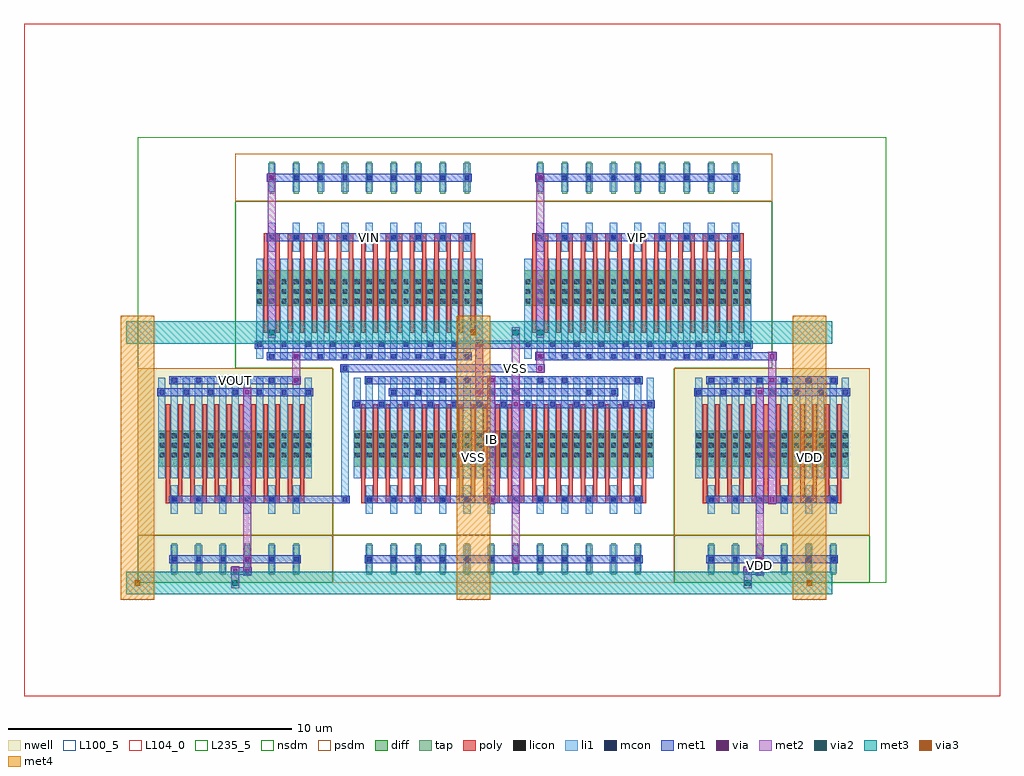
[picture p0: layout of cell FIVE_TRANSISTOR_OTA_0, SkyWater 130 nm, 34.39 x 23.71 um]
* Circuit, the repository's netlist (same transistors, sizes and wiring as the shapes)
* NGSPICE file created from FIVE_TRANSISTOR_OTA_0.ext - technology: sky130A

.subckt DCL_PMOS_S_13688038_X6_Y1_1774869037 a_200_252# w_0_0#
X0 w_0_0# a_200_252# a_200_252# w_0_0# sky130_fd_pr__pfet_01v8 ad=0.1764 pd=1.54 as=0.1764 ps=1.54 w=1.26 l=0.15 M=12
.ends

.subckt SCM_NMOS_16984956_X6_Y1_1774869040 a_402_441# a_200_252# a_147_441#
X0 a_147_441# a_200_252# a_200_252# a_147_441# sky130_fd_pr__nfet_01v8 ad=0.1764 pd=1.54 as=0.1764 ps=1.54 w=1.26 l=0.15 M=12
X1 a_147_441# a_200_252# a_402_441# a_147_441# sky130_fd_pr__nfet_01v8 ad=0.1764 pd=1.54 as=0.1764 ps=1.54 w=1.26 l=0.15 M=12
.ends

.subckt NMOS_4T_73049722_X9_Y1_1774869038 a_230_441# a_200_252# a_147_441# a_241_1232#
X0 a_147_441# a_200_252# a_230_441# a_241_1232# sky130_fd_pr__nfet_01v8 ad=0.1764 pd=1.54 as=0.1764 ps=1.54 w=1.26 l=0.15 M=18
.ends

.subckt PMOS_S_86315193_X6_Y1_1774869039 a_230_441# a_200_252# w_0_0#
X0 w_0_0# a_200_252# a_230_441# w_0_0# sky130_fd_pr__pfet_01v8 ad=0.1764 pd=1.54 as=0.1764 ps=1.54 w=1.26 l=0.15 M=12
.ends

.subckt FIVE_TRANSISTOR_OTA_0 IB VOUT VIP VIN VSS VDD
XDCL_PMOS_S_13688038_X6_Y1_1774869037_0 li_1437_571# VDD DCL_PMOS_S_13688038_X6_Y1_1774869037
XSCM_NMOS_16984956_X6_Y1_1774869040_0 m1_2376_1316# IB VSS SCM_NMOS_16984956_X6_Y1_1774869040
XNMOS_4T_73049722_X9_Y1_1774869038_0 VOUT VIN m1_2376_1316# VSS NMOS_4T_73049722_X9_Y1_1774869038
XNMOS_4T_73049722_X9_Y1_1774869038_1 li_1437_571# VIP m1_2376_1316# VSS NMOS_4T_73049722_X9_Y1_1774869038
XPMOS_S_86315193_X6_Y1_1774869039_0 VOUT li_1437_571# VDD PMOS_S_86315193_X6_Y1_1774869039
.ends

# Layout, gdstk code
from math import pi, radians
import gdstk
lib = gdstk.Library(unit=1e-6, precision=1e-09)
def R(c, l, rs):  # rectangles x0, y0, x1, y1
    for r in rs: c.add(gdstk.rectangle(r[:2], r[2:], *l))
def A(c, l, x, y, w, h, nx, ny, dx, dy):  # array of equal rectangles
    R(c, l, [(x+i*dx, y+j*dy, x+i*dx+w, y+j*dy+h) for i in range(nx) for j in range(ny)])
def P(c, l, *ps):  # polygons
    for p in ps: c.add(gdstk.Polygon(p, *l))
nwell = (64, 20)
diff = (65, 20)
tap = (65, 44)
poly = (66, 20)
licon = (66, 44)
li1 = (67, 20)
mcon = (67, 44)
met1 = (68, 20)
via = (68, 44)
met2 = (69, 20)
via2 = (69, 44)
met3 = (70, 20)
via3 = (70, 44)
met4 = (71, 20)
nsdm = (93, 44)
psdm = (94, 20)
L100_5 = (100, 5)
L104_0 = (104, 0)
L235_5 = (235, 5)

scm_nmos_16984956_x6_y1_ = lib.new_cell('SCM_NMOS_16984956_X6_Y1_1774869040')
R(scm_nmos_16984956_x6_y1_, diff, [(0.735,2.205,11.305,3.465)])
A(scm_nmos_16984956_x6_y1_, tap, 1.205, 6.16, 0.17, 1.12, 12, 1, 0.86, 0)
A(scm_nmos_16984956_x6_y1_, poly, 1, 1.26, 0.15, 3.36, 24, 1, 0.43, 0)
A(scm_nmos_16984956_x6_y1_, poly, 1, 4.485, 0.58, 0.27, 12, 1, 0.86, 0)
A(scm_nmos_16984956_x6_y1_, licon, 0.775, 2.285, 0.17, 0.17, 3, 3, 0.43, 0.34)
A(scm_nmos_16984956_x6_y1_, licon, 1.635, 2.285, 0.17, 0.17, 3, 3, 0.43, 0.34)
A(scm_nmos_16984956_x6_y1_, licon, 2.495, 2.285, 0.17, 0.17, 3, 3, 0.43, 0.34)
A(scm_nmos_16984956_x6_y1_, licon, 3.355, 2.285, 0.17, 0.17, 3, 3, 0.43, 0.34)
A(scm_nmos_16984956_x6_y1_, licon, 4.215, 2.285, 0.17, 0.17, 3, 3, 0.43, 0.34)
A(scm_nmos_16984956_x6_y1_, licon, 5.075, 2.285, 0.17, 0.17, 3, 3, 0.43, 0.34)
A(scm_nmos_16984956_x6_y1_, licon, 5.935, 2.285, 0.17, 0.17, 3, 3, 0.43, 0.34)
A(scm_nmos_16984956_x6_y1_, licon, 6.795, 2.285, 0.17, 0.17, 3, 3, 0.43, 0.34)
A(scm_nmos_16984956_x6_y1_, licon, 7.655, 2.285, 0.17, 0.17, 3, 3, 0.43, 0.34)
A(scm_nmos_16984956_x6_y1_, licon, 8.515, 2.285, 0.17, 0.17, 3, 3, 0.43, 0.34)
A(scm_nmos_16984956_x6_y1_, licon, 9.375, 2.285, 0.17, 0.17, 3, 3, 0.43, 0.34)
A(scm_nmos_16984956_x6_y1_, licon, 10.235, 2.285, 0.17, 0.17, 3, 3, 0.43, 0.34)
A(scm_nmos_16984956_x6_y1_, licon, 1.205, 4.535, 0.17, 0.17, 12, 2, 0.86, 2.1)
A(scm_nmos_16984956_x6_y1_, li1, 0.735, 0.335, 0.25, 3.53, 25, 1, 0.43, 0)
A(scm_nmos_16984956_x6_y1_, li1, 1.165, 4.115, 0.25, 1.01, 12, 2, 0.86, 2.1)
A(scm_nmos_16984956_x6_y1_, mcon, 0.775, 1.175, 0.17, 0.17, 13, 1, 0.86, 0)
A(scm_nmos_16984956_x6_y1_, mcon, 1.205, 4.535, 0.17, 0.17, 12, 2, 0.86, 2.1)
R(scm_nmos_16984956_x6_y1_, mcon, [(1.205,0.335,1.375,0.505), (3.785,0.335,3.955,0.505), (4.645,0.335,4.815,0.505), (7.225,0.335,7.395,0.505), (8.085,0.335,8.255,0.505), (10.665,0.335,10.835,0.505), (2.065,0.755,2.235,0.925), (2.925,0.755,3.095,0.925), (5.505,0.755,5.675,0.925), (6.365,0.755,6.535,0.925), (8.945,0.755,9.115,0.925), (9.805,0.755,9.975,0.925)])
R(scm_nmos_16984956_x6_y1_, met1, [(1.12,0.28,10.92,0.56), (1.98,0.7,10.06,0.98), (0.69,1.12,11.35,1.4), (1.12,4.48,10.92,4.76), (1.12,6.58,10.92,6.86)])
R(scm_nmos_16984956_x6_y1_, via, [(5.515,0.345,5.665,0.495), (6.375,1.185,6.525,1.335), (5.515,4.545,5.665,4.695), (6.375,6.645,6.525,6.795)])
R(scm_nmos_16984956_x6_y1_, met2, [(5.45,0.26,5.73,4.78), (6.31,1.1,6.59,6.88)])
R(scm_nmos_16984956_x6_y1_, nsdm, [(0,0,12.04,5.88)])
R(scm_nmos_16984956_x6_y1_, psdm, [(0,5.88,12.04,7.56)])
R(scm_nmos_16984956_x6_y1_, L100_5, [(0,0,12.04,7.56)])

dcl_pmos_s_13688038_x6_y = lib.new_cell('DCL_PMOS_S_13688038_X6_Y1_1774869037')
R(dcl_pmos_s_13688038_x6_y, nwell, [(0,0,6.88,7.56)])
R(dcl_pmos_s_13688038_x6_y, diff, [(0.735,2.205,6.145,3.465)])
A(dcl_pmos_s_13688038_x6_y, tap, 1.205, 6.16, 0.17, 1.12, 6, 1, 0.86, 0)
A(dcl_pmos_s_13688038_x6_y, poly, 1, 1.26, 0.15, 3.36, 12, 1, 0.43, 0)
A(dcl_pmos_s_13688038_x6_y, poly, 1, 4.485, 0.58, 0.27, 6, 1, 0.86, 0)
A(dcl_pmos_s_13688038_x6_y, licon, 0.775, 2.285, 0.17, 0.17, 3, 3, 0.43, 0.34)
A(dcl_pmos_s_13688038_x6_y, licon, 1.635, 2.285, 0.17, 0.17, 3, 3, 0.43, 0.34)
A(dcl_pmos_s_13688038_x6_y, licon, 2.495, 2.285, 0.17, 0.17, 3, 3, 0.43, 0.34)
A(dcl_pmos_s_13688038_x6_y, licon, 3.355, 2.285, 0.17, 0.17, 3, 3, 0.43, 0.34)
A(dcl_pmos_s_13688038_x6_y, licon, 4.215, 2.285, 0.17, 0.17, 3, 3, 0.43, 0.34)
A(dcl_pmos_s_13688038_x6_y, licon, 5.075, 2.285, 0.17, 0.17, 3, 3, 0.43, 0.34)
A(dcl_pmos_s_13688038_x6_y, licon, 1.205, 4.535, 0.17, 0.17, 6, 2, 0.86, 2.1)
A(dcl_pmos_s_13688038_x6_y, li1, 0.735, 0.335, 0.25, 3.53, 13, 1, 0.43, 0)
A(dcl_pmos_s_13688038_x6_y, li1, 1.165, 4.115, 0.25, 1.01, 6, 2, 0.86, 2.1)
A(dcl_pmos_s_13688038_x6_y, mcon, 1.205, 0.335, 0.17, 0.17, 6, 2, 0.86, 4.2)
A(dcl_pmos_s_13688038_x6_y, mcon, 0.775, 0.755, 0.17, 0.17, 7, 1, 0.86, 0)
A(dcl_pmos_s_13688038_x6_y, mcon, 1.205, 6.635, 0.17, 0.17, 6, 1, 0.86, 0)
R(dcl_pmos_s_13688038_x6_y, met1, [(1.12,0.28,5.76,0.56), (0.69,0.7,6.19,0.98), (1.12,4.48,5.76,4.76), (1.12,6.58,5.76,6.86)])
R(dcl_pmos_s_13688038_x6_y, via, [(3.365,0.345,3.515,0.495), (3.795,0.765,3.945,0.915), (3.365,4.545,3.515,4.695), (3.795,6.645,3.945,6.795)])
R(dcl_pmos_s_13688038_x6_y, met2, [(3.3,0.26,3.58,4.78), (3.73,0.68,4.01,6.88)])
R(dcl_pmos_s_13688038_x6_y, nsdm, [(0,5.88,6.88,7.56)])
R(dcl_pmos_s_13688038_x6_y, psdm, [(0,0,6.88,5.88)])
R(dcl_pmos_s_13688038_x6_y, L100_5, [(0,0,6.88,7.56)])

pmos_s_86315193_x6_y1_17 = lib.new_cell('PMOS_S_86315193_X6_Y1_1774869039')
R(pmos_s_86315193_x6_y1_17, nwell, [(0,0,6.88,7.56)])
R(pmos_s_86315193_x6_y1_17, diff, [(0.735,2.205,6.145,3.465)])
A(pmos_s_86315193_x6_y1_17, tap, 1.205, 6.16, 0.17, 1.12, 6, 1, 0.86, 0)
A(pmos_s_86315193_x6_y1_17, poly, 1, 1.26, 0.15, 3.36, 12, 1, 0.43, 0)
A(pmos_s_86315193_x6_y1_17, poly, 1, 4.485, 0.58, 0.27, 6, 1, 0.86, 0)
A(pmos_s_86315193_x6_y1_17, licon, 0.775, 2.285, 0.17, 0.17, 3, 3, 0.43, 0.34)
A(pmos_s_86315193_x6_y1_17, licon, 1.635, 2.285, 0.17, 0.17, 3, 3, 0.43, 0.34)
A(pmos_s_86315193_x6_y1_17, licon, 2.495, 2.285, 0.17, 0.17, 3, 3, 0.43, 0.34)
A(pmos_s_86315193_x6_y1_17, licon, 3.355, 2.285, 0.17, 0.17, 3, 3, 0.43, 0.34)
A(pmos_s_86315193_x6_y1_17, licon, 4.215, 2.285, 0.17, 0.17, 3, 3, 0.43, 0.34)
A(pmos_s_86315193_x6_y1_17, licon, 5.075, 2.285, 0.17, 0.17, 3, 3, 0.43, 0.34)
A(pmos_s_86315193_x6_y1_17, licon, 1.205, 4.535, 0.17, 0.17, 6, 2, 0.86, 2.1)
A(pmos_s_86315193_x6_y1_17, li1, 0.735, 0.335, 0.25, 3.53, 13, 1, 0.43, 0)
A(pmos_s_86315193_x6_y1_17, li1, 1.165, 4.115, 0.25, 1.01, 6, 2, 0.86, 2.1)
A(pmos_s_86315193_x6_y1_17, mcon, 1.205, 0.335, 0.17, 0.17, 6, 2, 0.86, 4.2)
A(pmos_s_86315193_x6_y1_17, mcon, 0.775, 0.755, 0.17, 0.17, 7, 1, 0.86, 0)
A(pmos_s_86315193_x6_y1_17, mcon, 1.205, 6.635, 0.17, 0.17, 6, 1, 0.86, 0)
R(pmos_s_86315193_x6_y1_17, met1, [(1.12,0.28,5.76,0.56), (0.69,0.7,6.19,0.98), (1.12,4.48,5.76,4.76), (1.12,6.58,5.76,6.86)])
R(pmos_s_86315193_x6_y1_17, via, [(3.795,0.765,3.945,0.915), (3.795,6.645,3.945,6.795)])
R(pmos_s_86315193_x6_y1_17, met2, [(3.73,0.68,4.01,6.88)])
R(pmos_s_86315193_x6_y1_17, nsdm, [(0,5.88,6.88,7.56)])
R(pmos_s_86315193_x6_y1_17, psdm, [(0,0,6.88,5.88)])
R(pmos_s_86315193_x6_y1_17, L100_5, [(0,0,6.88,7.56)])

nmos_4t_73049722_x9_y1_1 = lib.new_cell('NMOS_4T_73049722_X9_Y1_1774869038')
R(nmos_4t_73049722_x9_y1_1, diff, [(0.735,2.205,8.725,3.465)])
A(nmos_4t_73049722_x9_y1_1, tap, 1.205, 6.16, 0.17, 1.12, 9, 1, 0.86, 0)
A(nmos_4t_73049722_x9_y1_1, poly, 1, 1.26, 0.15, 3.36, 18, 1, 0.43, 0)
A(nmos_4t_73049722_x9_y1_1, poly, 1, 4.485, 0.58, 0.27, 9, 1, 0.86, 0)
A(nmos_4t_73049722_x9_y1_1, licon, 0.775, 2.285, 0.17, 0.17, 3, 3, 0.43, 0.34)
A(nmos_4t_73049722_x9_y1_1, licon, 1.635, 2.285, 0.17, 0.17, 3, 3, 0.43, 0.34)
A(nmos_4t_73049722_x9_y1_1, licon, 2.495, 2.285, 0.17, 0.17, 3, 3, 0.43, 0.34)
A(nmos_4t_73049722_x9_y1_1, licon, 3.355, 2.285, 0.17, 0.17, 3, 3, 0.43, 0.34)
A(nmos_4t_73049722_x9_y1_1, licon, 4.215, 2.285, 0.17, 0.17, 3, 3, 0.43, 0.34)
A(nmos_4t_73049722_x9_y1_1, licon, 5.075, 2.285, 0.17, 0.17, 3, 3, 0.43, 0.34)
A(nmos_4t_73049722_x9_y1_1, licon, 5.935, 2.285, 0.17, 0.17, 3, 3, 0.43, 0.34)
A(nmos_4t_73049722_x9_y1_1, licon, 6.795, 2.285, 0.17, 0.17, 3, 3, 0.43, 0.34)
A(nmos_4t_73049722_x9_y1_1, licon, 7.655, 2.285, 0.17, 0.17, 3, 3, 0.43, 0.34)
A(nmos_4t_73049722_x9_y1_1, licon, 1.205, 4.535, 0.17, 0.17, 9, 2, 0.86, 2.1)
A(nmos_4t_73049722_x9_y1_1, li1, 0.735, 0.335, 0.25, 3.53, 19, 1, 0.43, 0)
A(nmos_4t_73049722_x9_y1_1, li1, 1.165, 4.115, 0.25, 1.01, 9, 2, 0.86, 2.1)
A(nmos_4t_73049722_x9_y1_1, mcon, 1.205, 0.335, 0.17, 0.17, 9, 2, 0.86, 4.2)
A(nmos_4t_73049722_x9_y1_1, mcon, 0.775, 0.755, 0.17, 0.17, 10, 1, 0.86, 0)
A(nmos_4t_73049722_x9_y1_1, mcon, 1.205, 6.635, 0.17, 0.17, 9, 1, 0.86, 0)
R(nmos_4t_73049722_x9_y1_1, met1, [(1.12,0.28,8.34,0.56), (0.69,0.7,8.77,0.98), (1.12,4.48,8.34,4.76), (1.12,6.58,8.34,6.86)])
R(nmos_4t_73049722_x9_y1_1, nsdm, [(0,0,9.46,5.88)])
R(nmos_4t_73049722_x9_y1_1, psdm, [(0,5.88,9.46,7.56)])
R(nmos_4t_73049722_x9_y1_1, L100_5, [(0,0,9.46,7.56)])

five_transistor_ota_0 = lib.new_cell('FIVE_TRANSISTOR_OTA_0')
R(five_transistor_ota_0, li1, [(7.185,2.855,7.435,3.025), (7.185,2.855,7.435,3.025), (7.185,2.855,7.435,3.025), (7.185,2.855,7.435,3.025), (7.185,2.94,7.435,7.56), (7.185,7.475,7.435,7.645), (7.185,7.475,7.435,7.645), (7.185,7.475,7.435,7.645), (7.185,7.475,7.435,7.645)])
R(five_transistor_ota_0, mcon, [(7.225,2.855,7.395,3.025), (7.225,2.855,7.395,3.025), (7.225,2.855,7.395,3.025), (7.225,2.855,7.395,3.025), (7.225,7.475,7.395,7.645), (7.225,7.475,7.395,7.645), (7.225,7.475,7.395,7.645), (7.225,7.475,7.395,7.645)])
R(five_transistor_ota_0, met1, [(3.28,0.28,3.6,0.56), (3.28,0.28,3.6,0.56), (3.44,0.28,3.87,0.56), (3.71,0.28,4.03,0.56), (3.71,0.28,4.03,0.56), (21.34,0.28,21.66,0.56), (21.34,0.28,21.66,0.56), (21.34,0.28,21.66,0.56), (21.5,0.28,21.93,0.56), (21.77,0.28,22.09,0.56), (21.77,0.28,22.09,0.56), (21.77,0.28,22.09,0.56), (5.59,2.8,7.31,3.08), (7.14,2.8,7.48,3.08), (7.14,2.8,7.48,3.08), (7.14,2.8,7.48,3.08), (7.14,2.8,7.48,3.08), (11.88,6.58,12.2,6.86), (11.88,6.58,12.2,6.86), (11.88,6.58,12.2,6.86), (11.88,6.58,12.2,6.86), (5.43,7,5.75,7.28), (5.43,7,5.75,7.28), (7.14,7.42,7.48,7.7), (7.14,7.42,7.48,7.7), (7.14,7.42,7.48,7.7), (7.14,7.42,7.48,7.7), (7.31,7.42,14.19,7.7), (14.03,7.42,14.35,7.7), (14.03,7.42,14.35,7.7), (14.03,7.42,14.35,7.7), (14.03,7.42,14.35,7.7), (5.43,7.84,5.75,8.12), (5.43,7.84,5.75,8.12), (14.03,7.84,14.35,8.12), (14.03,7.84,14.35,8.12), (14.03,7.84,14.35,8.12), (14.03,7.84,14.35,8.12), (21.07,7.84,22.36,8.12), (22.2,7.84,22.52,8.12), (22.2,7.84,22.52,8.12), (11.88,8.26,12.2,8.54), (11.88,8.26,12.2,8.54), (11.88,8.26,12.2,8.54), (11.88,8.26,12.2,8.54), (12.04,8.26,13.76,8.54), (4.57,14.14,4.89,14.42), (4.57,14.14,4.89,14.42), (14.03,14.14,14.35,14.42), (14.03,14.14,14.35,14.42), (14.03,14.14,14.35,14.42)])
P(five_transistor_ota_0, met1, [(0,0),(0,0),(0,0),(0,0)],
  [(0,0),(0,0),(0,0),(0,0)],
  [(0,0),(0,0),(0,0),(0,0)],
  [(0,0),(0,0),(0,0),(0,0)],
  [(0,0),(0,0),(0,0),(0,0)],
  [(0,0),(0,0),(0,0),(0,0)],
  [(0,0),(0,0),(0,0),(0,0)],
  [(0,0),(0,0),(0,0),(0,0)],
  [(0,0),(0,0),(0,0),(0,0)],
  [(0,0),(0,0),(0,0),(0,0)],
  [(0,0),(0,0),(0,0),(0,0)],
  [(0,0),(0,0),(0,0),(0,0)],
  [(0,0),(0,0),(0,0),(0,0)],
  [(0,0),(0,0),(0,0),(0,0)])
R(five_transistor_ota_0, via, [(3.365,0.345,3.515,0.495), (3.365,0.345,3.515,0.495), (3.795,0.345,3.945,0.495), (3.795,0.345,3.945,0.495), (21.425,0.345,21.575,0.495), (21.425,0.345,21.575,0.495), (21.425,0.345,21.575,0.495), (21.855,0.345,22.005,0.495), (21.855,0.345,22.005,0.495), (21.855,0.345,22.005,0.495), (11.965,6.645,12.115,6.795), (11.965,6.645,12.115,6.795), (11.965,6.645,12.115,6.795), (11.965,6.645,12.115,6.795), (5.515,7.065,5.665,7.215), (5.515,7.065,5.665,7.215), (14.115,7.485,14.265,7.635), (14.115,7.485,14.265,7.635), (14.115,7.485,14.265,7.635), (14.115,7.485,14.265,7.635), (5.515,7.905,5.665,8.055), (5.515,7.905,5.665,8.055), (14.115,7.905,14.265,8.055), (14.115,7.905,14.265,8.055), (14.115,7.905,14.265,8.055), (14.115,7.905,14.265,8.055), (22.285,7.905,22.435,8.055), (22.285,7.905,22.435,8.055), (11.965,8.325,12.115,8.475), (11.965,8.325,12.115,8.475), (11.965,8.325,12.115,8.475), (11.965,8.325,12.115,8.475), (4.655,14.205,4.805,14.355), (4.655,14.205,4.805,14.355), (14.115,14.205,14.265,14.355), (14.115,14.205,14.265,14.355), (14.115,14.205,14.265,14.355)])
R(five_transistor_ota_0, met2, [(3.3,-0.185,3.58,0.185), (3.3,-0.185,3.58,0.185), (21.36,-0.185,21.64,0.185), (21.36,-0.185,21.64,0.185), (21.36,-0.185,21.64,0.185), (3.3,0,3.58,0.42), (21.36,0,21.64,0.42), (3.3,0.26,3.58,0.58), (3.3,0.26,3.58,0.58), (3.73,0.26,4.01,0.58), (3.73,0.26,4.01,0.58), (21.36,0.26,21.64,0.58), (21.36,0.26,21.64,0.58), (21.36,0.26,21.64,0.58), (21.79,0.26,22.07,0.58), (21.79,0.26,22.07,0.58), (21.79,0.26,22.07,0.58), (3.73,0.42,4.01,0.84), (21.79,0.42,22.07,0.84), (13.19,6.3,13.47,8.82), (11.9,6.56,12.18,6.88), (11.9,6.56,12.18,6.88), (11.9,6.56,12.18,6.88), (11.9,6.56,12.18,6.88), (11.9,6.72,12.18,8.4), (5.45,6.98,5.73,7.3), (5.45,6.98,5.73,7.3), (5.45,7.14,5.73,7.98), (22.22,7.14,22.5,7.98), (14.05,7.4,14.33,7.72), (14.05,7.4,14.33,7.72), (14.05,7.4,14.33,7.72), (14.05,7.4,14.33,7.72), (14.05,7.56,14.33,7.98), (5.45,7.82,5.73,8.14), (5.45,7.82,5.73,8.14), (14.05,7.82,14.33,8.14), (14.05,7.82,14.33,8.14), (14.05,7.82,14.33,8.14), (14.05,7.82,14.33,8.14), (22.22,7.82,22.5,8.14), (22.22,7.82,22.5,8.14), (11.9,8.24,12.18,8.56), (11.9,8.24,12.18,8.56), (11.9,8.24,12.18,8.56), (11.9,8.24,12.18,8.56), (4.59,8.635,4.87,9.005), (4.59,8.635,4.87,9.005), (13.19,8.635,13.47,9.005), (13.19,8.635,13.47,9.005), (13.19,8.635,13.47,9.005), (13.19,8.635,13.47,9.005), (14.05,8.635,14.33,9.005), (14.05,8.635,14.33,9.005), (14.05,8.635,14.33,9.005), (4.59,8.82,4.87,14.28), (14.05,8.82,14.33,14.28), (4.59,14.12,4.87,14.44), (4.59,14.12,4.87,14.44), (14.05,14.12,14.33,14.44), (14.05,14.12,14.33,14.44), (14.05,14.12,14.33,14.44)])
P(five_transistor_ota_0, met2, [(0,0),(0,0),(0,0),(0,0)],
  [(0,0),(0,0),(0,0),(0,0)],
  [(0,0),(0,0),(0,0),(0,0)],
  [(0,0),(0,0),(0,0),(0,0)],
  [(0,0),(0,0),(0,0),(0,0)],
  [(0,0),(0,0),(0,0),(0,0)])
R(five_transistor_ota_0, via2, [(3.34,-0.1,3.54,0.1), (3.34,-0.1,3.54,0.1), (21.4,-0.1,21.6,0.1), (21.4,-0.1,21.6,0.1), (21.4,-0.1,21.6,0.1), (4.63,8.72,4.83,8.92), (4.63,8.72,4.83,8.92), (13.23,8.72,13.43,8.92), (13.23,8.72,13.43,8.92), (13.23,8.72,13.43,8.92), (13.23,8.72,13.43,8.92), (14.09,8.72,14.29,8.92), (14.09,8.72,14.29,8.92), (14.09,8.72,14.29,8.92)])
A(five_transistor_ota_0, met3, -0.4, -0.4, 4.24, 0.8, 3, 2, 3.44, 8.82)
R(five_transistor_ota_0, met3, [(-0.165,-0.4,0.165,0.4), (3.275,-0.4,3.605,0.4), (3.275,-0.4,3.605,0.4), (9.92,-0.4,12.24,0.4), (11.44,-0.4,14.16,0.4), (13.36,-0.4,17.6,0.4), (16.8,-0.4,21.04,0.4), (20.24,-0.4,24.08,0.4), (21.335,-0.4,21.665,0.4), (21.335,-0.4,21.665,0.4), (21.335,-0.4,21.665,0.4), (23.28,-0.4,24.48,0.4), (23.515,-0.4,23.845,0.4), (4.565,8.42,4.895,9.22), (4.565,8.42,4.895,9.22), (9.92,8.42,12.24,9.22), (11.44,8.42,14.16,9.22), (11.675,8.42,12.005,9.22), (13.165,8.42,13.495,9.22), (13.165,8.42,13.495,9.22), (13.165,8.42,13.495,9.22), (13.165,8.42,13.495,9.22), (13.36,8.42,17.6,9.22), (14.025,8.42,14.355,9.22), (14.025,8.42,14.355,9.22), (14.025,8.42,14.355,9.22), (16.8,8.42,21.04,9.22), (20.24,8.42,24.08,9.22), (23.28,8.42,24.48,9.22)])
R(five_transistor_ota_0, via3, [(-0.1,-0.1,0.1,0.1), (23.58,-0.1,23.78,0.1), (11.74,8.72,11.94,8.92)])
A(five_transistor_ota_0, met4, -0.59, -0.59, 1.18, 10, 3, 1, 11.84, 0)
R(five_transistor_ota_0, met4, [(-0.59,-0.165,0.59,0.165), (23.09,-0.165,24.27,0.165), (11.25,8.655,12.43,8.985)])
R(five_transistor_ota_0, L104_0, [(-4,-4,30.39,19.71)])
R(five_transistor_ota_0, L235_5, [(0,0,26.39,15.71)])
five_transistor_ota_0.add(gdstk.Reference(scm_nmos_16984956_x6_y1_, (6.88,7.56), x_reflection=True))
five_transistor_ota_0.add(gdstk.Reference(dcl_pmos_s_13688038_x6_y, (25.8,7.56), rotation=pi))
five_transistor_ota_0.add(gdstk.Reference(pmos_s_86315193_x6_y1_17, (0,7.56), x_reflection=True))
five_transistor_ota_0.add(gdstk.Reference(nmos_4t_73049722_x9_y1_1, (12.9,7.56)))
five_transistor_ota_0.add(gdstk.Reference(nmos_4t_73049722_x9_y1_1, (12.9,7.56), rotation=pi, x_reflection=True))
five_transistor_ota_0.add(gdstk.Label('IB', (12.47,5.04), layer=69, texttype=5))
five_transistor_ota_0.add(gdstk.Label('VOUT', (3.44,7.14), layer=68, texttype=5))
five_transistor_ota_0.add(gdstk.Label('VIP', (17.63,12.18), layer=68, texttype=5))
five_transistor_ota_0.add(gdstk.Label('VIN', (8.17,12.18), layer=68, texttype=5))
five_transistor_ota_0.add(gdstk.Label('VSS', (13.33,7.56), layer=69, texttype=5))
five_transistor_ota_0.add(gdstk.Label('VSS', (11.84,4.41), layer=71, texttype=5))
five_transistor_ota_0.add(gdstk.Label('VSS', (11.84,4.41), layer=71, texttype=5))
five_transistor_ota_0.add(gdstk.Label('VSS', (11.84,4.41), layer=71, texttype=5))
five_transistor_ota_0.add(gdstk.Label('VSS', (11.84,4.41), layer=71, texttype=5))
five_transistor_ota_0.add(gdstk.Label('VSS', (11.84,4.41), layer=71, texttype=5))
five_transistor_ota_0.add(gdstk.Label('VSS', (11.84,4.41), layer=71, texttype=5))
five_transistor_ota_0.add(gdstk.Label('VSS', (11.84,4.41), layer=71, texttype=5))
five_transistor_ota_0.add(gdstk.Label('VSS', (11.84,4.41), layer=71, texttype=5))
five_transistor_ota_0.add(gdstk.Label('VDD', (21.93,0.63), layer=69, texttype=5))
five_transistor_ota_0.add(gdstk.Label('VDD', (23.68,4.41), layer=71, texttype=5))
five_transistor_ota_0.add(gdstk.Label('VDD', (23.68,4.41), layer=71, texttype=5))
five_transistor_ota_0.add(gdstk.Label('VDD', (23.68,4.41), layer=71, texttype=5))
five_transistor_ota_0.add(gdstk.Label('VDD', (23.68,4.41), layer=71, texttype=5))
five_transistor_ota_0.add(gdstk.Label('VDD', (23.68,4.41), layer=71, texttype=5))
five_transistor_ota_0.add(gdstk.Label('VDD', (23.68,4.41), layer=71, texttype=5))
five_transistor_ota_0.add(gdstk.Label('VDD', (23.68,4.41), layer=71, texttype=5))
five_transistor_ota_0.add(gdstk.Label('VDD', (23.68,4.41), layer=71, texttype=5))

lib.write_gds('FIVE_TRANSISTOR_OTA_0.gds')
